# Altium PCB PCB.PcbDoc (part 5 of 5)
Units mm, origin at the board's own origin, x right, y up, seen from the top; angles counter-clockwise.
Board outline 101.6 x 53.34 mm, 6 copper layers (Top Layer, Int1 (GND), Int2, Int3, Int4 (GND), Bottom Layer), stack 1.625 mm thick; 228 components, 228 nets, 1016 pads, 998 vias.

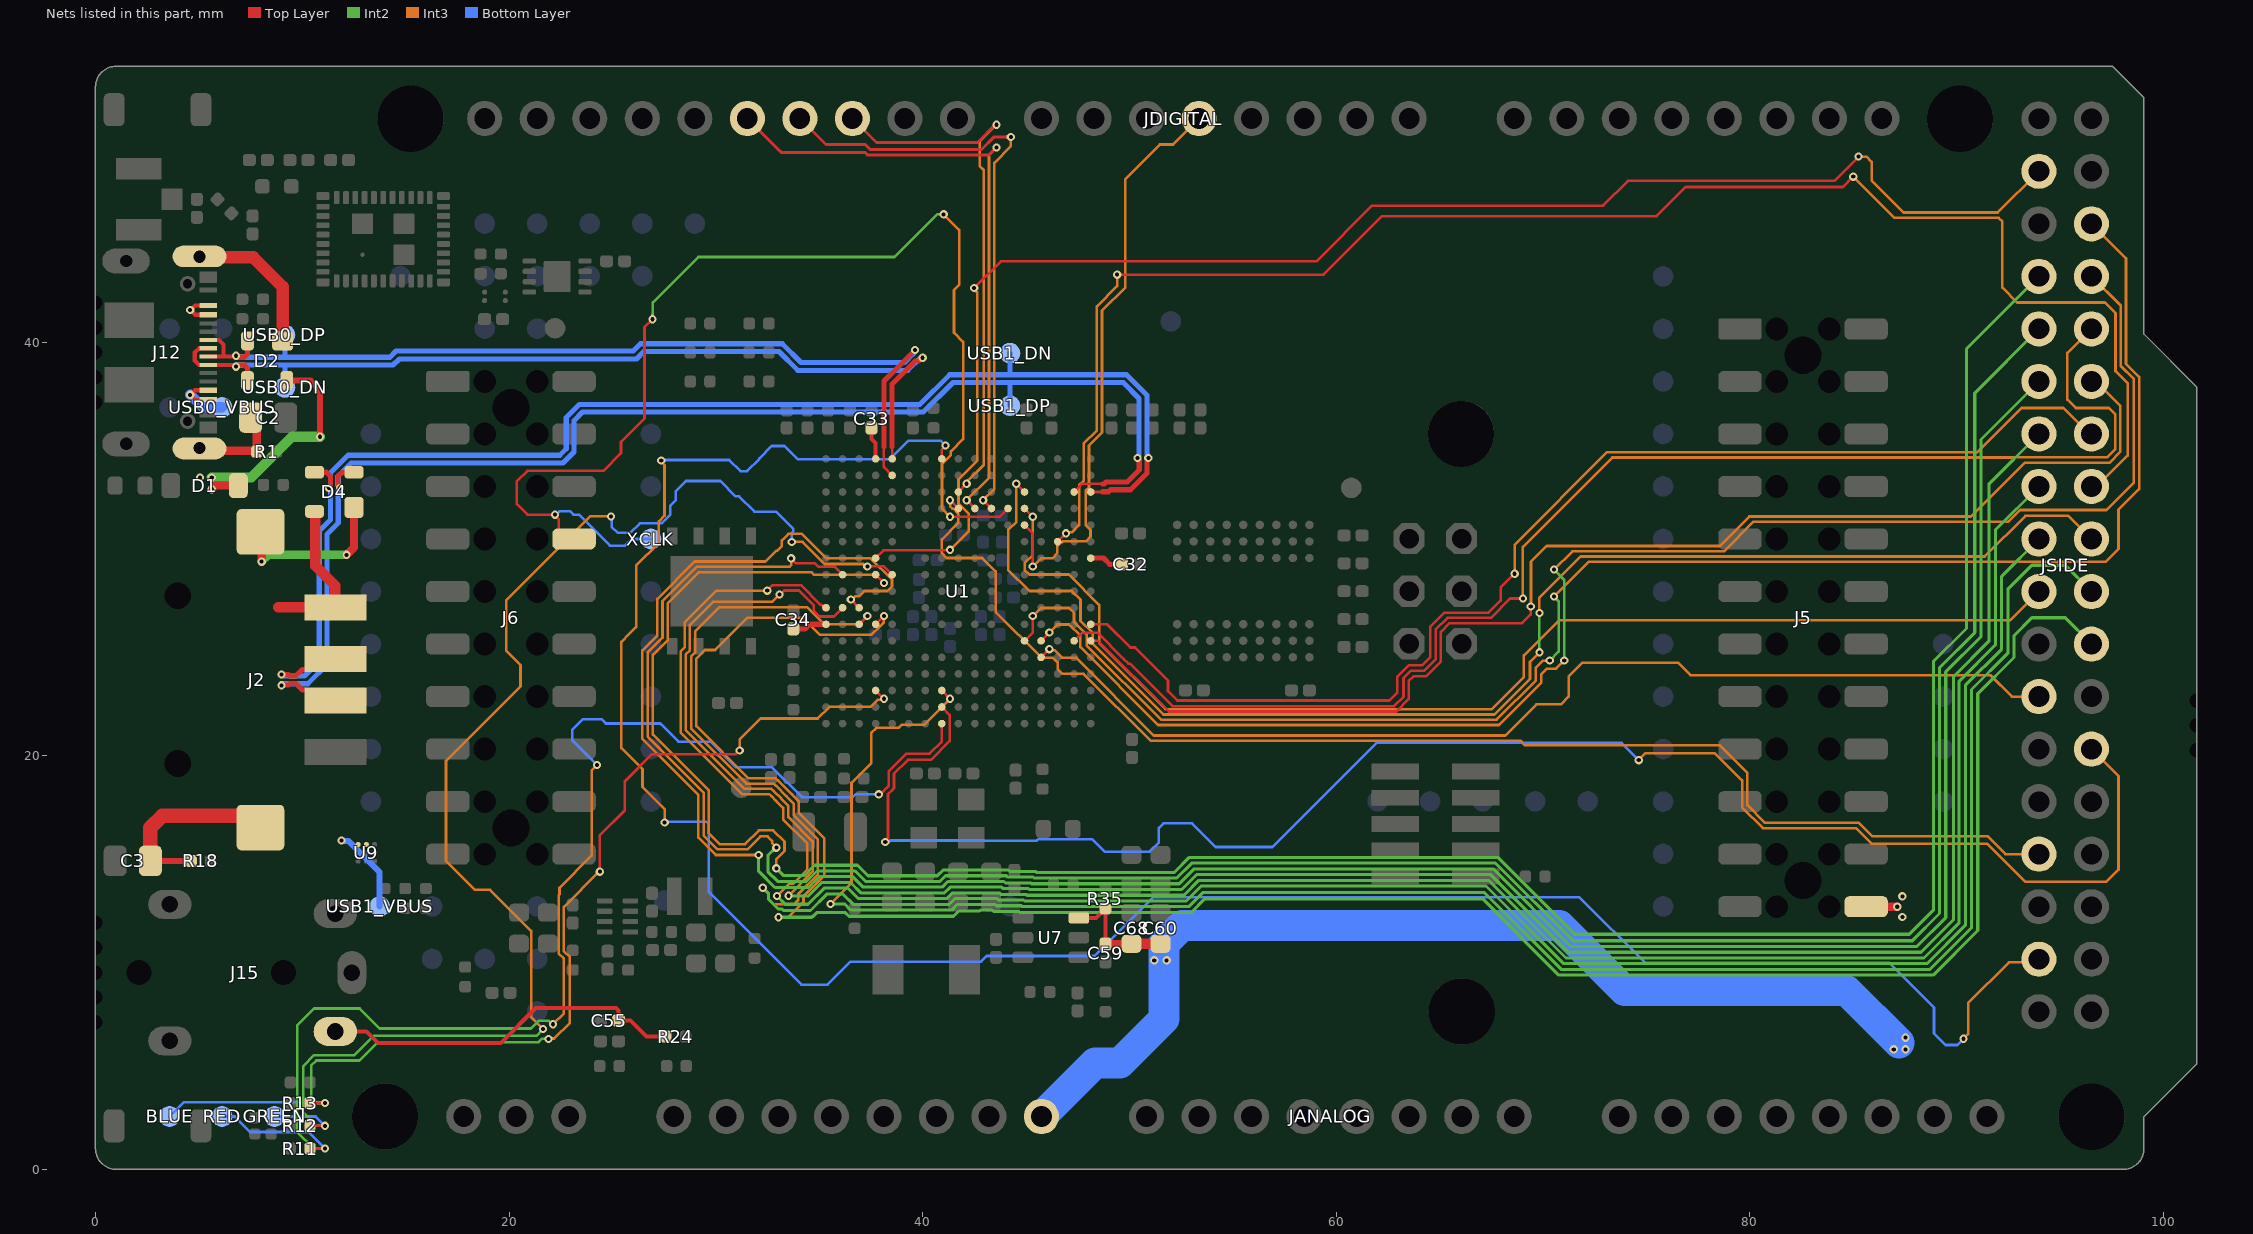
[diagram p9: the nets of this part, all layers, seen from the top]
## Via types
v1: diameter 0.4, hole 0.2, Top Layer to Bottom Layer, tented both sides, 998 vias

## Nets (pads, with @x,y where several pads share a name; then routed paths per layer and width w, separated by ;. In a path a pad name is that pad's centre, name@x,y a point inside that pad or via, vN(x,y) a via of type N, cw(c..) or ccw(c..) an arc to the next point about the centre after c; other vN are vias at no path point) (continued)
PI13: JSIDE.26 U1.H2 | length 82.6
  Top Layer w0.127: v1(38.192,15.823) 38.192,15.897 38.326,16.031 38.326,18.139 38.539,18.351 38.539,18.354 38.614,18.429 38.614,19.133 39.281,19.8 40.4,19.8 41.302,20.702 41.302,21.977 U1.H2@40.926,22.353
  Int3 w0.127: v1(74.626,19.785) 74.963,20.123 78.301,20.123 79.625,18.799 79.625,17.505 80.632,16.499 85.125,16.499 85.875,15.749 91.475,15.749 93.325,13.899 97.234,13.899 97.825,14.489 97.825,19.013 JSIDE.26@96.52,20.319
  Bottom Layer w0.127: v1(38.192,15.823) 38.244,15.875 38.417,15.875 38.44,15.898 42.903,15.898 42.909,15.892 45.514,15.892 45.59,15.967 48.188,15.967 48.8,15.356 50.971,15.356 51.418,15.802 51.418,16.515 51.634,16.732 53.023,16.732 54.169,15.586 56.911,15.586 61.943,20.618 73.793,20.618 v1(74.626,19.785)
PI14: JSIDE.20 U1.H3 | length 94.4
  Top Layer w0.127: U1.H3@40.926,23.153 v1(41.326,22.753)
  Int2 w0.15: v1(35.547,12.83) 36.234,12.83 36.529,12.534 41.402,12.534 41.679,12.811 42.684,12.811 43.477,12.812 43.547,12.742 44.765,12.742 44.809,12.698 52.866,12.698 53.543,13.376 67.172,13.376 70.882,9.667 88.713,9.667 90.722,11.675 90.722,23.199 92.474,24.952 92.474,28.047 93.636,29.209 95.25,29.209 JSIDE.20@96.52,27.939
  Int3 w0.127: v1(35.547,12.83) 36.042,13.324 36.56,13.842 36.56,18.686 37.505,19.632 37.505,21.091 37.76,21.346 38.84,21.346 38.987,21.493 40.067,21.493 v1(41.326,22.753)
PI15: JSIDE.23 U1.P5 | length 52.9
  Top Layer w0.127: U1.P5@45.726,24.753 v1(46.126,25.153)
  Int3 w0.127: v1(46.126,25.153) 46.177,25.102 46.373,25.102 46.732,24.743 47.407,24.743 51.174,20.977 68.177,20.977 69.682,22.481 70.86,22.481 71.235,22.856 71.235,23.836 71.897,24.499 76.525,24.499 77.125,23.899 91.625,23.899 92.665,22.859 JSIDE.23@93.98,22.859
PJ0: JSIDE.6 U1.N6 | length 79.6
  Top Layer w0.127: U1.N6@44.926,25.553 45.326,25.953 v1(45.326,26.753)
  Int2 w0.127: v1(70.325,24.599) 70.325,24.61 70.755,25.04 70.755,27.468 v1(70.525,27.699)
  Int3 w0.127: v1(45.326,26.753) 45.717,27.143 47.088,27.143 47.317,26.915 47.317,26.474 47.933,25.858 47.933,25.34 51.534,21.739 67.76,21.739 69.652,23.631 69.652,24.258 69.993,24.599 v1(70.325,24.599) ; v1(70.525,27.699) 72.205,29.378 97.205,29.378 97.825,29.999 97.825,31.899 98.823,32.896 98.823,38.318 98.19,38.951 98.19,44.049 JSIDE.6@96.52,45.719
PJ1: JSIDE.8 U1.P6 | length 74.7
  Top Layer w0.127: U1.P6@45.726,25.553 v1(46.126,25.953)
  Int2 w0.127: v1(70.525,28.999) 71.025,28.499 v1(71.025,24.599)
  Int3 w0.127: v1(46.126,25.953) 46.517,26.343 47.088,26.343 47.623,25.808 47.623,25.246 51.384,21.485 67.865,21.485 69.906,23.526 69.906,23.93 70.184,24.208 70.635,24.208 v1(71.025,24.599) ; v1(70.525,28.999) 71.413,29.886 78.746,29.886 80.175,31.315 92.504,31.315 93.071,31.882 97.235,31.882 98.569,33.216 98.569,38.213 97.936,38.846 97.936,41.763 JSIDE.8@96.52,43.179
PJ2: JSIDE.10 U1.T6 | length 68.2
  Top Layer w0.127: U1.T6@47.326,25.553 47.726,25.953 48.447,25.953 49.719,24.68 49.948,24.452 50.023,24.452 52.083,22.392 62.797,22.392 63.251,22.845 63.251,23.756 63.607,24.112 64.257,24.112 64.803,24.658 64.803,26.093 65.372,26.662 67.473,26.662 68.409,27.599 v1(69.025,27.599)
  Int3 w0.127: v1(69.025,27.599) 69.025,30.099 73.348,34.422 92.843,34.422 92.858,34.437 97.29,34.437 97.666,34.813 97.666,36.513 97.366,36.813 95.766,36.813 95.354,37.224 95.354,39.473 JSIDE.10@96.52,40.639
PJ3: JSIDE.12 U1.U6 | length 63.4
  Top Layer w0.127: U1.U6@48.126,25.553 48.487,25.553 51.903,22.138 62.903,22.138 63.505,22.74 63.505,23.607 63.739,23.841 64.345,23.841 65.057,24.553 65.057,25.988 65.477,26.408 68.985,26.408 69.404,26.827 v1(69.404,27.215)
  Int3 w0.127: v1(69.404,27.215) 69.416,27.227 69.416,29.389 70.167,30.14 78.547,30.14 79.976,31.569 90.696,31.569 93.291,34.164 97.381,34.164 97.92,34.703 97.92,36.909 96.73,38.099 JSIDE.12@96.52,38.099
PJ4: JSIDE.14 U1.U7 | length 59.1
  Top Layer w0.127: U1.U7@48.126,26.353 48.926,26.353 50.047,25.233 50.272,25.233 51.866,23.638 51.866,23.118 52.312,22.672 62.577,22.672 62.956,23.051 62.956,23.821 63.501,24.366 64.152,24.366 64.549,24.763 64.549,26.236 65.229,26.916 67.368,26.916 67.953,27.502 67.953,28.127 v1(68.625,28.799)
  Int3 w0.127: v1(68.625,28.799) 68.625,30.199 73.102,34.676 91.002,34.676 93.139,36.813 95.166,36.813 96.42,35.559 JSIDE.14@96.52,35.559
PJ5: JSIDE.16 U1.R12 | length 78.6
  Top Layer w0.127: U1.R12@46.526,30.353 v1(46.926,30.753) ; v1(49.406,43.261) 59.39,43.261 62.219,46.09 75.49,46.09 76.9,47.5 84.5,47.5 v1(85,48)
  Int3 w0.127: v1(46.926,30.753) 46.978,30.805 47.226,30.805 47.571,31.15 47.571,33.083 47.782,33.294 47.782,35.094 48.421,35.734 48.421,41.724 49.406,42.709 v1(49.406,43.261) ; v1(85,48) 86.988,46.012 92.029,46.012 92.21,45.83 92.21,42.63 92.928,41.913 97.166,41.913 97.682,41.396 97.682,38.596 98.266,38.013 98.266,34.513 96.772,33.019 JSIDE.16@96.52,33.019
PJ6: JSIDE.18 U1.N15 | length 67.6
  Top Layer w0.127: v1(44.526,33.153) 44.709,32.97 U1.N15@44.922,32.757
  Int2 w0.127: v1(69.825,24.999) v1(69.825,26.899)
  Int3 w0.127: v1(44.526,33.153) 44.526,31.305 44.136,30.915 44.136,28.991 45.164,27.962 47.088,27.962 47.099,27.974 47.205,27.974 47.635,27.543 47.635,26.515 48.226,25.924 48.226,25.407 51.639,21.993 67.655,21.993 69.368,23.706 69.368,24.542 v1(69.825,24.999) ; v1(69.825,26.899) 69.825,27.644 71.813,29.632 91.359,29.632 93.325,31.599 95.4,31.599 JSIDE.18@96.52,30.479
PJ7: JSIDE.19 U1.N14 | length 59.2
  Top Layer w0.127: U1.N14@44.926,31.953 v1(45.326,31.553)
  Int3 w0.127: v1(45.326,31.553) 45.326,29.705 44.936,29.315 44.936,28.991 45.164,28.762 47.069,28.762 48.539,27.292 48.539,25.452 51.745,22.247 67.526,22.247 69.075,23.796 69.075,24.849 70.775,26.548 92.59,26.548 JSIDE.19@93.98,27.939
PJ8: JDIGITAL.14 U1.N13 | length 28.7
  Top Layer w0.127: U1.N13@44.926,31.153 45.326,30.753 v1(45.326,29.153)
  Int3 w0.127: v1(45.326,29.153) 45.717,29.543 46.269,29.543 46.517,29.791 46.517,30.148 46.682,30.313 46.734,30.313 46.783,30.362 47.888,30.362 48.117,30.591 48.117,30.915 47.882,31.15 47.882,32.813 48.042,32.974 48.042,34.996 48.675,35.629 48.675,41.521 49.797,42.642 49.797,47.883 51.47,49.557 52.11,49.557 JDIGITAL.14@53.366,50.813
PJ9: J6.8 U1.M14 XCLK.X | length 58.3
  Top Layer w0.127: J6.8@22.863,30.5 22.822,30.5 22.411,30.911 22.411,31.427 22.217,31.62 v1(22.217,31.658) 20.891,31.658 20.38,32.169 20.38,33.275 20.881,33.775 24.555,33.775 25.412,34.633 25.412,35.179 26.547,36.314 26.547,40.72 v1(26.931,41.104) ; v1(41.326,31.553) 43.726,31.553 U1.M14@44.126,31.953
  Int2 w0.127: v1(26.931,41.104) 26.931,41.335 26.952,41.356 26.952,41.914 29.156,44.118 38.638,44.118 40.698,46.178 v1(41.016,46.178)
  Int3 w0.127: v1(41.016,46.178) 41.768,45.425 41.768,42.771 41.516,42.518 41.516,40.458 41.962,40.012 41.962,35.31 41.36,34.707 41.36,34.539 40.936,34.115 40.936,31.944 v1(41.326,31.553)
  Bottom Layer w0.127: v1(22.217,31.658) 22.274,31.658 22.428,31.812 22.963,31.812 23.117,31.658 23.383,31.658 24.88,30.16 25.603,30.16 25.921,30.479 XCLK.X@26.862,30.479
PJ10: JDIGITAL.7 U1.L14 | length 29.8
  Top Layer w0.127: v1(42.926,32.353) U1.L14@43.326,31.953
  Top Layer w0.15: JDIGITAL.7@34.062,50.813 35.322,49.552 37.227,49.552 37.462,49.317 42.843,49.317 43.439,49.913 v1(44.266,49.913)
  Int3 w0.127: v1(42.926,32.353) 43.462,32.889 43.462,48.668 44.266,49.471 v1(44.266,49.913)
PJ11: JDIGITAL.6 U1.K14 | length 31.2
  Top Layer w0.127: v1(42.126,32.353) U1.K14@42.526,31.953
  Top Layer w0.15: JDIGITAL.6@31.522,50.813 33.022,49.313 33.156,49.178 37.209,49.178 37.348,49.04 43.193,49.04 v1(43.566,49.413)
  Int3 w0.127: v1(42.126,32.353) 43.208,33.435 43.208,49.055 v1(43.566,49.413)
PJ12: JSIDE.3 U1.D11 | length 74
  Top Layer w0.127: U1.D11@37.726,29.553 38.102,29.928 41.302,29.928 v1(41.326,29.953) ; v1(42.49,42.613) 43.783,43.906 59.034,43.906 61.727,46.598 72.899,46.598 74.1,47.8 84.1,47.8 85.258,48.958 v1(85.258,48.971)
  Int3 w0.127: v1@41.326,29.953 42.226,30.853 42.226,31.701 41.736,32.191 41.736,33.363 42.635,34.262 42.635,42.402 42.49,42.547 v1(42.49,42.613) ; v1(85.258,48.971) 85.638,48.971 85.89,48.719 85.89,47.809 87.434,46.266 91.987,46.266 JSIDE.3@93.98,48.259
PJ14: JSIDE.7 U1.D10 | length 122
  Top Layer w0.127: U1.D10@37.726,28.753 v1(38.126,28.353)
  Int2 w0.15: v1(32.926,14.553) 33.281,14.198 34.268,14.198 34.772,14.703 36.852,14.703 37.358,14.196 40.714,14.196 40.991,14.473 41.997,14.473 ; 41.997,14.474 44.165,14.474 44.235,14.404 45.454,14.404 45.497,14.36 52.177,14.36 52.899,15.082 67.817,15.082 71.535,11.364 87.71,11.364 88.874,12.528 88.874,17.448 88.874,24.552 90.474,26.152 90.474,39.673 JSIDE.7@93.98,43.179
  Int3 w0.127: v1(32.926,14.553) 32.926,15.001 33.317,15.391 33.317,15.845 32.775,16.387 32.078,16.387 31.414,15.723 30.187,15.723 29.66,16.249 29.66,18.315 26.952,21.023 26.952,24.877 27.317,25.242 27.676,25.601 27.676,27.376 29.179,28.88 34.616,28.88 34.752,28.744 37.736,28.744 v1@38.151,28.328
PJ15: JSIDE.9 U1.B10 | length 118.6
  Top Layer w0.127: v1(33.642,29.544) 33.886,29.299 34.782,29.299 34.952,29.128 35.751,29.128 U1.B10@36.126,28.753
  Int2 w0.15: v1(32.926,15.553) 32.895,15.553 32.515,15.174 32.515,14.395 32.989,13.921 34.382,13.921 34.887,14.426 36.737,14.426 37.243,13.919 40.828,13.919 41.105,14.196 42.112,14.196 ; 42.112,14.197 44.051,14.197 44.12,14.127 45.339,14.127 45.383,14.083 52.292,14.083 53.013,14.805 67.702,14.805 71.455,11.052 87.855,11.052 89.174,12.371 89.174,24.252 90.874,25.952 90.874,37.533 JSIDE.9@93.98,40.639
  Int3 w0.127: 27.063,25.347 26.698,24.982 26.698,20.917 29.406,18.21 29.406,16.144 30.081,15.469 31.519,15.469 32.153,16.103 32.497,16.103 32.726,15.874 32.726,15.777 32.926,15.577 v1(32.926,15.553) ; 27.063,25.348 27.422,25.707 27.422,27.482 29.074,29.134 33.554,29.134 33.642,29.221 v1(33.642,29.544)
PK0: JSIDE.29 U1.J14 | length 64.9
  Top Layer w0.127: v1(41.326,32.353) U1.J14@41.726,31.953
  Int3 w0.127: v1@41.326,32.253 41.326,32.053 41.435,31.943 41.488,31.943 41.717,31.715 41.717,31.244 40.926,30.453 40.926,29.801 41.164,29.562 42.875,29.562 43.526,28.912 43.526,26.953 45.735,24.743 46.288,24.743 46.526,24.505 46.526,24.201 46.764,23.962 47.785,23.962 51.024,20.723 68.91,20.723 69.13,20.503 78.549,20.503 79.879,19.173 79.879,17.61 80.737,16.753 85.271,16.753 85.925,16.099 91.505,16.099 92.365,15.239 JSIDE.29@93.98,15.239
PK1: JDIGITAL.8 U1.J15 | length 26.5
  Top Layer w0.127: U1.J15@41.726,32.753 v1(42.126,33.153)
  Top Layer w0.15: JDIGITAL.8@36.602,50.813 37.765,49.65 42.655,49.65 43.518,50.513 v1(43.566,50.513)
  Int3 w0.127: v1(42.126,33.153) 42.126,33.227 42.954,34.055 42.954,48.317 42.753,48.518 42.753,49.7 v1(43.566,50.513)
PK2: JSIDE.33 U1.H17 | length 114.9
  Top Layer w0.127: U1.H17@40.926,34.353 40.926,34.801 41.1,34.975 v1(41.1,35)
  Int3 w0.127: v1(27.36,34.274) 27.36,34.215 27.517,34.059 27.517,31.61 27.24,31.333 27.24,30.293 26.145,29.198 26.145,26.226 25.793,25.874 25.428,25.508 25.428,20.367 26.45,19.346 26.45,18.493 27.524,17.419 v1(27.524,16.769) ; v1(90.334,6.31) 90.556,6.532 90.556,8.03 92.53,10.003 93.824,10.003 JSIDE.33@93.98,10.159
  Bottom Layer w0.127: v1(27.36,34.274) 27.385,34.299 30.641,34.299 31.184,33.756 31.507,33.756 32.105,34.354 32.105,34.379 32.702,34.977 33.318,34.977 33.951,34.343 38.429,34.343 39.318,35.232 40.868,35.232 v1(41.1,35) ; v1(27.524,16.769) 27.565,16.81 29.549,16.81 29.66,16.698 29.66,13.408 34.139,8.929 35.41,8.929 36.521,10.04 42.825,10.04 43.097,10.311 46.559,10.311 48.309,10.311 51.147,13.15 71.759,13.15 74.92,9.989 86.736,9.989 88.907,7.818 88.907,6.571 89.466,6.013 90.037,6.013 v1(90.334,6.31)
PK3: JSIDE.11 U1.C8 | length 122.4
  Top Layer w0.127: v1(36.526,27.553) U1.C8@36.926,27.153
  Int2 w0.15: v1(32.068,15.195) 32.068,14.411 32.851,13.629 33.16,13.629 33.681,13.629 34.481,13.629 35.001,14.149 36.622,14.149 37.129,13.642 40.943,13.642 41.22,13.919 42.226,13.919 43.936,13.92 44.006,13.85 45.224,13.85 45.268,13.806 52.407,13.806 53.128,14.528 67.588,14.528 71.341,10.775 88.078,10.775 89.474,12.171 89.474,24.052 91.174,25.752 91.174,35.293 JSIDE.11@93.98,38.099
  Int3 w0.127: 26.809,25.452 26.444,25.088 26.444,20.812 29.152,18.104 29.152,16.039 29.996,15.195 v1(32.068,15.195) ; 26.809,25.453 27.168,25.812 27.168,27.587 28.969,29.388 32.402,29.388 32.931,29.917 32.969,29.917 33.191,30.138 33.191,30.409 33.511,30.729 34.159,30.729 35.345,29.543 37.488,29.543 38.517,28.515 38.517,28.191 38.288,27.962 37.183,27.962 36.929,27.709 36.737,27.709 36.582,27.553 v1(36.526,27.553)
PK4: JSIDE.13 U1.B8 | length 110.6
  Top Layer w0.127: v1(33.082,27.797) 33.121,27.797 33.314,27.99 34.011,27.99 34.738,27.263 34.738,26.994 35.003,26.729 35.702,26.729 U1.B8@36.126,27.153
  Int2 w0.15: v1(33.515,13.227) 33.532,13.21 34.454,13.21 35.116,13.872 36.507,13.872 37.014,13.365 41.058,13.365 41.335,13.642 42.341,13.642 ; 42.342,13.643 43.821,13.643 43.891,13.573 45.109,13.573 45.153,13.529 52.521,13.529 53.243,14.251 67.473,14.251 71.226,10.498 88.279,10.498 89.845,12.063 89.845,23.822 91.574,25.552 91.574,33.153 JSIDE.13@93.98,35.559
  Int3 w0.127: v1(33.082,27.797) 32.725,27.44 29.85,27.44 28.741,26.331 28.741,25.098 28.549,24.907 28.549,21.222 31.375,18.396 32.685,18.396 32.784,18.297 32.793,18.297 33.171,17.92 33.171,17.911 33.504,17.578 33.504,17.027 34.678,15.853 34.678,14.39 v1(33.515,13.227)
PK5: JSIDE.15 U1.A8 | length 108.7
  Top Layer w0.127: v1(32.485,27.981) 32.748,28.244 34.116,28.244 35.061,27.299 35.114,27.299 35.26,27.153 U1.A8@35.326,27.153
  Int2 w0.15: v1(32.955,13.215) 33.355,12.814 34.459,12.814 35.239,13.595 36.393,13.595 36.899,13.088 41.173,13.088 41.45,13.365 42.456,13.365 43.706,13.366 43.776,13.296 44.995,13.296 45.038,13.252 52.636,13.252 53.357,13.973 67.359,13.973 71.111,10.221 88.419,10.221 90.122,11.923 90.122,23.599 91.874,25.352 91.874,30.913 JSIDE.15@93.98,33.019
  Int3 w0.127: v1(32.485,27.981) 30.032,27.981 28.487,26.436 28.487,25.237 28.293,25.044 28.293,21.118 31.27,18.142 32.58,18.142 32.679,18.043 32.688,18.043 32.917,17.815 32.917,17.805 33.25,17.473 33.25,16.922 34.424,15.748 34.424,14.495 33.749,13.821 33.556,13.821 32.955,13.219 v1(32.955,13.215)
PK6: JSIDE.17 U1.C7 | length 111.2
  Top Layer w0.127: U1.C7@36.926,26.353 v1(37.326,26.753)
  Int2 w0.15: v1(32.267,13.613) 32.553,13.327 32.553,13.048 33.013,12.587 33.194,12.587 33.233,12.548 33.241,12.548 33.272,12.517 34.573,12.517 35.363,13.306 36.149,13.306 36.644,12.811 41.287,12.811 41.564,13.088 42.57,13.088 ; 42.57,13.089 43.592,13.089 43.661,13.019 44.88,13.019 44.924,12.975 52.751,12.975 53.472,13.696 67.244,13.696 70.997,9.944 88.566,9.944 90.422,11.799 90.422,23.399 92.174,25.152 92.174,28.673 JSIDE.17@93.98,30.479
  Int3 w0.127: v1(32.267,13.613) 32.564,13.316 32.564,13.053 32.798,12.819 33.774,12.819 33.984,13.029 33.984,13.308 34.932,14.256 34.932,15.959 33.758,17.133 33.758,17.683 33.425,18.016 33.425,18.025 32.898,18.551 32.889,18.551 32.791,18.65 31.48,18.65 28.803,21.327 28.803,24.802 28.995,24.993 28.995,26.011 30.17,27.186 34.406,27.186 35.23,26.362 36.936,26.362 v1(37.326,26.753)
PK7: JSIDE.22 U1.D7 | length 109
  Top Layer w0.127: U1.D7@37.726,26.353 v1(38.126,26.753)
  Int2 w0.15: v1(33.034,12.185) 34.634,12.185 34.683,12.235 34.707,12.235 34.881,12.408 36.264,12.408 36.437,12.235 41.494,12.235 41.748,12.488 42.753,12.488 42.8,12.535 43.362,12.535 43.432,12.465 44.65,12.465 44.694,12.421 52.98,12.421 53.637,13.078 67.078,13.078 70.767,9.39 88.861,9.39 91.022,11.551 91.022,22.999 92.774,24.752 92.774,25.807 93.636,26.669 95.25,26.669 JSIDE.22@96.52,25.399
  Int3 w0.127: v1(33.034,12.185) 33.5,12.185 34.238,12.924 34.238,13.203 35.246,14.211 35.246,16.003 34.012,17.238 34.012,17.788 33.679,18.121 33.679,18.13 33.004,18.805 32.994,18.805 32.896,18.904 31.586,18.904 29.057,21.432 29.057,24.696 29.47,25.11 29.962,25.11 31.53,26.678 34.196,26.678 35.02,25.854 37.528,25.854 37.926,26.253 38.126,26.453 v1(38.126,26.753)
R_7: C55.2 J15.3 R24.2 | length 17.8
  Top Layer w0.2: J15.3@11.6,6.663 13.097,6.663 13.66,6.1 19.6,6.1 21.292,7.792 25.173,7.792 25.29,7.675 C55.2@25.29,7.19 25.87,7.19 26.641,6.419 R24.2@27.585,6.419
RGB_BLUE_1: BLUE.X R13.2 U1.D3 | length 52.3
  Top Layer w0.127: R13.2@10.375,3.2 v1(11.1,3.2) ; v1(24.389,14.392) 24.389,16.154 25.594,17.36 25.594,18.745 26.919,20.071 30.958,20.071 31.138,20.25 v1(31.15,20.25) ; U1.D3@37.726,23.153 v1(38.126,22.753)
  Int2 w0.127: v1(11.1,3.2) 10.71,3.2 10.43,3.48 10.43,5.011 10.68,5.261 12.761,5.261 13.65,6.15 21.422,6.15 21.577,6.304 v1(21.904,6.304)
  Int3 w0.127: v1(21.904,6.304) 21.925,6.325 22.182,6.325 22.936,7.079 22.936,10.257 22.65,10.543 22.65,12.694 24.348,14.392 v1(24.389,14.392) ; v1(31.15,20.25) 31.15,20.792 32.157,21.798 34.922,21.798 35.486,22.362 37.488,22.362 37.827,22.701 38.075,22.701 v1(38.126,22.753)
  Bottom Layer w0.127: BLUE.X@3.582,2.553 4.272,3.243 11.057,3.243 v1(11.1,3.2)
RGB_GREEN_1: GREEN.X R12.2 U1.E10 | length 69
  Top Layer w0.127: R12.2@10.375,2.1 v1(11.1,2.1) ; v1(37.326,29.153) 38.126,29.153 U1.E10@38.526,28.753
  Int2 w0.127: v1(11.1,2.1) 10.7,2.1 10.05,2.75 10.05,4.99 10.575,5.515 12.515,5.515 13.45,6.45 21.316,6.45 v1(21.644,6.779)
  Int3 w0.127: v1(21.644,6.779) 21.069,7.354 21.069,11.521 19.081,13.509 18.36,13.509 16.953,14.916 16.953,19.753 20.555,23.355 20.555,24.384 19.87,25.069 19.87,27.524 23.918,31.572 v1(24.933,31.572) ; v1(33.672,30.338) 34.191,30.338 35.26,29.269 37.136,29.269 37.252,29.153 v1(37.326,29.153)
  Bottom Layer w0.127: GREEN.X@8.662,2.553 10.647,2.553 v1(11.1,2.1) ; v1(24.933,31.572) 24.959,31.545 24.959,31.07 25.248,30.782 25.865,30.782 26.322,31.238 27.381,31.238 27.787,31.645 27.787,32.082 28.061,32.355 28.061,32.793 28.551,33.283 30.22,33.283 30.96,32.543 31.13,32.543 31.87,31.804 32.898,31.804 33.748,30.953 33.748,30.848 33.672,30.772 v1(33.672,30.338)
RGB_RED_1: R11.2 RED.X U1.H1 | length 64.4
  Top Layer w0.127: R11.2@10.375,1 v1(11.1,1) ; v1(37.877,18.132) 37.951,18.132 38.106,18.287 38.116,18.287 38.285,18.457 38.285,18.46 38.36,18.535 38.36,19.238 39.222,20.1 40.341,20.1 40.926,20.685 U1.H1@40.926,21.553
  Int2 w0.127: v1(11.1,1) 10.56,1 9.75,1.81 9.75,6.95 10.572,7.772 12.777,7.772 13.739,6.81 21.06,6.81 21.432,7.182 21.92,7.182 22.085,7.017 v1(22.127,7.017)
  Int3 w0.127: v1(22.127,7.017) 22.65,7.54 22.65,10.184 22.396,10.438 22.396,13.244 22.44,13.288 22.44,13.612 23.993,15.165 23.993,19.293 v1(24.25,19.55)
  Bottom Layer w0.127: RED.X@6.122,2.553 6.731,2.553 7.482,1.802 10.298,1.802 v1(11.1,1) ; v1(24.25,19.55) 23.05,20.75 23.05,21.25 23.567,21.767 24.47,21.767 24.681,21.555 27.31,21.555 27.335,21.531 27.344,21.531 28.193,20.682 29.736,20.682 30.98,19.438 32.725,19.438 34.173,17.991 36.618,17.991 36.759,18.132 v1(37.877,18.132)
SHIELD1a_3: C3.2 J2.SHIELD2 R18.2 | length 9.2
  Top Layer w0.3: C3.2@2.655,14.913 R18.2@4.731,14.913
  Top Layer w0.7: C3.2@2.655,14.913 2.655,16.519 3.24,17.105 J2.SHIELD2@7.92,17.105
SHIELD1b_3: D4.1 J2.SHIELD1 | length 8.2
  Top Layer w0.4: J2.SHIELD1@7.98,30.825 8.036,30.769 v1(8.036,29.383) ; v1(12.142,29.713) 12.501,30.072 D4.1@12.501,32.01
  Int2 w0.4: v1(8.036,29.383) 8.365,29.713 v1(12.142,29.713)
USB0_D_N: D2.3 J12.A7 J12.B7 U1.E17 USB0_DN.X | length 45.3
  Top Layer w0.127: 38.515,34.937 38.526,34.925 U1.E17@38.526,34.353
  Top Layer w0.2: J12.B7@5.454,39.7 5.008,39.7 4.802,39.494 4.802,39.106 5.008,38.9 J12.A7@5.454,38.9 6.657,38.9 6.746,38.812 v1(6.8,38.812)
  Top Layer w0.25: v1(6.8,38.812) 6.814,38.812 6.889,38.887 7.2,38.887 7.35,38.737 D2.3@7.35,38.145 ; 38.515,34.937 38.515,37.959 39.071,38.515 39.635,39.079 39.792,39.079 39.959,39.245 v1(40,39.245)
  Bottom Layer w0.25: v1@6.775,38.887 9.163,38.887 ; USB0_DN.X@9.163,37.809 9.163,38.887 ; v1(40,39.245) 39.971,39.217 39.865,39.217 39.283,38.635 33.96,38.635 33.052,39.542 26.515,39.542 26.163,39.19 14.695,39.19 14.391,38.887 9.163,38.887
USB0_D_P: D2.2 J12.A6 J12.B6 U1.E16 USB0_DP.X | length 45.9
  Top Layer w0.127: 38.138,34.937 38.126,34.925 38.126,33.953 U1.E16@38.526,33.553
  Top Layer w0.2: J12.B6@5.454,39.3 6.191,39.3 ; J12.A6@5.454,40.1 5.979,40.1 6.191,39.888 6.191,39.3 ; v1@6.707,39.3 6.191,39.3 ; v1@6.708,39.3 v1@6.87,39.3
  Top Layer w0.25: v1(6.8,39.339) 6.841,39.339 6.916,39.264 7.2,39.264 7.35,39.413 D2.2@7.35,40.055 ; 38.138,34.937 38.138,38.115 38.915,38.892 v1@39.627,39.604
  Bottom Layer w0.25: v1@6.775,39.264 9.163,39.264 ; USB0_DP.X@9.163,40.349 9.163,39.264 ; v1(39.627,39.618) 39.627,39.577 39.548,39.498 39.548,39.433 39.127,39.012 34.117,39.012 33.209,39.919 26.359,39.919 26.006,39.567 14.539,39.567 14.235,39.264 9.163,39.264
USB0_SHIELD1_3: D2.1 J12.SHIELD1 | length 7.2
  Top Layer w0.6: J12.SHIELD1@5.029,44.12 5.052,44.097 7.629,44.097 9.05,42.676 D2.1@9.05,40.055
USB0_SHIELD2_3: C2.2 J12.SHIELD2 R1.2 | length 4.7
  Top Layer w0.4: J12.SHIELD2@5.029,34.88 5.167,34.742 7.725,34.742 7.798,34.669 7.798,34.661 7.798,36.052 C2.2@7.5,36.35
USB1_D_N: D4.3 J2.2 U1.U15 USB1_DN.X | length 66.1
  Top Layer w0.127: U1.U15@48.126,32.753 48.698,32.753 48.71,32.764
  Top Layer w0.25: v1(9,23.927) 9.326,23.927 9.39,23.863 9.701,23.863 10.012,24.175 J2.2@11.6,24.175 ; D4.3@10.591,33.71 11.17,33.71 11.358,33.523 v1@11.358,33.125 ; 48.71,32.764 48.991,32.764 49.087,32.86 50.054,32.86 50.854,33.661 v1@50.854,34.222
  Bottom Layer w0.25: v1(9,23.927) 9.041,23.927 9.116,23.852 10.111,23.852 10.822,24.563 10.822,30.869 11.366,31.413 11.366,32.828 11.287,32.907 v1(11.287,32.948) 11.287,32.988 11.366,33.068 11.366,33.679 12.216,34.529 18.792,34.529 22.454,34.529 22.767,34.841 22.767,36.357 23.4,36.99 39.877,36.99 41.309,38.422 44.161,38.422 ; USB1_DN.X@44.221,39.463 44.221,38.482 44.161,38.422 ; v1(50.912,34.392) 50.884,34.421 50.884,34.527 50.844,34.566 50.844,35.272 50.844,37.431 49.854,38.422 44.161,38.422
USB1_D_P: D4.2 J2.3 U1.T15 USB1_DP.X | length 66.1
  Top Layer w0.127: U1.T15@47.326,32.753 47.726,33.153 48.698,33.153 48.71,33.141
  Top Layer w0.25: v1(9,23.4) 9.021,23.421 9.325,23.421 9.39,23.486 9.701,23.486 10.012,23.175 J2.3@11.6,23.175 ; v1(11.822,32.948) 11.822,32.988 11.735,33.076 11.735,33.523 11.922,33.71 D4.2@12.501,33.71 ; 48.71,33.141 48.777,33.141 48.873,33.237 49.898,33.237 50.477,33.817 v1@50.477,34.26
  Bottom Layer w0.25: v1(9,23.4) 9.041,23.4 9.116,23.475 10.268,23.475 11.199,24.406 11.199,30.713 11.743,31.257 11.743,32.828 11.822,32.907 v1(11.822,32.948) 11.822,32.988 11.743,33.068 11.743,33.523 12.372,34.152 18.636,34.152 22.61,34.152 23.144,34.685 23.144,36.201 23.556,36.613 40.033,36.613 41.465,38.045 44.261,38.045 ; USB1_DP.X@44.221,36.923 44.221,38.005 44.261,38.045 ; v1(50.385,34.392) 50.385,34.433 50.467,34.515 50.467,35.428 50.467,37.275 49.698,38.045 44.261,38.045
VBUS_USB0: D1.A D2.4 J12.A4 J12.A9 J12.B4 J12.B9 USB0_VBUS.X | length 17.1
  Top Layer w0.2: J12.A9@5.454,37.225 4.804,37.225 v1(4.579,37.45) 4.804,37.675 J12.B4@5.454,37.675 ; J12.B9@5.454,41.325 4.804,41.325 v1(4.579,41.55) 4.804,41.775 J12.A4@5.454,41.775
  Top Layer w0.3: D2.4@9.25,38.145 10.384,38.145 10.854,37.675 v1(10.854,35.425)
  Top Layer w0.4: v1(5.622,32.887) 5.797,33.062 D1.A@6.91,33.062
  Int2 w0.5: v1(5.622,33.453) 7.532,33.453 9.504,35.425 v1(10.854,35.425)
  Bottom Layer w0.5: v1(4.579,37.45) 5.186,36.843 USB0_VBUS.X@6.122,36.843
  other v1: 5.056,33.453
VBUS_USB1: D4.4 J2.1 U9.A3 U9.B3 USB1_VBUS.X | length 11.9
  Top Layer w0.5: 8.825,27.175 J2.1@11.6,27.175 11.6,28.213 10.622,29.191 D4.4@10.622,31.81
  Bottom Layer w0.3: v1(11.9,15.9) 11.919,15.881 12.231,15.881 13.742,14.37 USB1_VBUS.X@13.742,12.713
VCAP_A7_5: C34.2 U1.A7 | length 1.7
  Top Layer w0.25: C34.2@33.746,26.133 34.306,26.133 34.526,26.353 U1.A7@35.326,26.353
VCAP_D17_5: C33.2 U1.D17 | length 1.5
  Top Layer w0.2: C33.2@37.532,35.747 37.532,35.317 37.726,35.123 U1.D17@37.726,34.353
VCAP_U11_5: C32.2 U1.U11 | length 1.6
  Top Layer w0.25: U1.U11@48.126,29.553 48.745,29.553 49.045,29.253 C32.2@49.621,29.253
VIN: C59.1 C60.2 C68.2 J5.24 JANALOG.8 R35.1 U7.3 | length 57.9
  Top Layer w0.2: U7.3@47.55,12.15 48.384,12.15 R35.1@48.831,12.597 ; C59.1@48.842,10.894 R35.1@48.842,12.587 ; 49.206,10.903 C68.2@50.1,10.903
  Top Layer w0.4: C59.1@48.842,10.894 50.091,10.894 C68.2@50.1,10.903 ; J5.24@85.725,12.699 v1(87.125,12.699)
  Top Layer w0.5: C68.2@50.1,10.903 C60.2@51.5,10.903
  Bottom Layer w1.5: JANALOG.8@45.755,2.562 48.337,5.144 49.539,5.144 51.672,7.277 51.672,10.923 52.548,11.799 70.787,11.799 73.944,8.642 84.682,8.642 87.205,6.119
  other v1: 86.96,5.799 87.525,5.799 87.525,6.364 51.2,10.104 51.8,10.104 87.375,12.199 87.375,13.199
pads on no net: Fiducial_1.1 Fiducial_2.1 Fiducial_3.1 Fiducial_4.1 Fiducial_5.1 J2.HOLES J5.0 J6.0 J8.6 J8.7 J8.8 J12.A8 J12.B8 J12.FIXING J12.SHIELD3 J12.SHIELD4 J15.NC1 J15.NC2 JANALOG.1 U1.E1 U3.E2 U4.1 U4.2 U4.3 U4.7 U4.9 U5.6 U5.7 U5.8 U5.9 U5.10 U5.11 U5.13 U5.15 U5.16 U5.17 U5.18 U6.6 U9.C1 Y3.2 Y3.4

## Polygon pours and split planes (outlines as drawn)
GND on Int2 "GND_L03_P012" (solid, remove dead copper, pour order 12): 0,1 0,52.34 cw(c1,52.34) 1,53.34 97.536,53.34 99.06,51.816 99.06,40.386 101.6,37.846 101.6,5.08 99.06,2.54 99.06,1 cw(c98.06,1) 98.06,0 1,0 cw(c1,1)
+3V3 on Int2 "+3V3_L03_P003" (solid, remove dead copper, pour order 3): 11.483,48.43 13.31,48.43 16.81,44.93 30.443,44.93 37.256,38.256 37.278,35.434 32.335,29.413 25.642,29.413 22.919,32.135 22.919,38.421 22.11,39.23 20.21,39.23 18.22,39.23 17.648,38.644 17.648,37.106 17.272,36.73 15.61,36.73 14.337,38.003 14.337,41.113 12.737,42.713 11.842,42.713 11.342,43.213 11.342,45.013 10.573,45.613 10.573,47.672
+3V3 on Int2 "+3V3_L03_P011" (solid, remove dead copper, pour order 11): 31.5,35.5 33,37 58,37 61,34 61,23.5 54,17.5 51.5,17.5 48.485,14.485 40.895,14.485 38.274,11.812 33.874,7.412 29.074,7.412 25.522,10.964 25.522,29.522
VBUS_USB0 on Int2 "VBUS_USB0_L03_P001" (solid, remove dead copper, pour order 1): 2.274,40.836 2.274,33.43 3.151,32.553 6.067,32.553 6.067,35.8 6.067,42.1 3.538,42.1
+5V on Int2 "+5V_L03_P032" (solid, remove dead copper, pour order 32): 97.11,52.43 98.21,51.33 98.21,47.03 97.182,46.002 88.21,46.002 88.21,48 90.279,48 93.78,51.5 93.78,52.172 94.038,52.43
GND on Top Layer "GND_L01_P036" (solid, remove dead copper, pour order 36): 0,1 0,52.34 cw(c1,52.34) 1,53.34 97.536,53.34 99.06,51.816 99.06,40.386 101.6,37.846 101.6,5.08 99.06,2.54 99.06,1 cw(c98.06,1) 98.06,0 1,0 cw(c1,1)
+5V on Top Layer "+5V_L01_P021" (solid, remove dead copper, pour order 21): 36.916,11.776 36.916,10.853 37.253,10.516 37.253,7.89 37.116,7.753 36.216,7.753 36.016,7.953 36.016,10.353 36.516,10.853 36.516,11.776
+3V3 on Top Layer "+3V3_L01_P019" (solid, pour order 19): 32.074,10.341 32.074,9.385 32.159,9.3 32.324,9.135 32.324,8.074 32.15,7.9 31.4,7.9 31.15,8.15 31.15,9.15 31.3,9.3 31.589,9.3 31.674,9.385 31.674,10.341
+3V3 on Top Layer "+3V3_L01_P029" (solid, remove dead copper, pour order 29): 76.675,14.088 76.675,13.695 77.372,12.999 79.86,12.999 79.86,12.413 76.213,12.413 74.913,13.713 74.913,14.101 75.056,14.245 76.519,14.245
VIN on Top Layer "VIN_L01_P025" (solid, remove dead copper, pour order 25): 85.725,12.999 86.825,12.999 87.225,13.399 87.725,13.399 87.925,13.199 87.925,12.199 87.725,11.999 87.225,11.999 86.825,12.399 85.725,12.399
+5V on Top Layer "+5V_L01_P022" (solid, remove dead copper, pour order 22): 77.874,16.19 77.874,15.797 78.219,15.452 79.874,15.452 79.874,14.952 76.974,14.952 76.112,15.814 76.112,16.203 76.255,16.347 77.718,16.347
VBUS_USB1 on Top Layer "POWER_POLY" (solid, remove dead copper, pour order 7): 12.4,27.8 12.4,26.547 9.247,26.547 7.832,25.132 7.832,22.868 11.706,18.994 12.268,18.994 13.3,17.962 13.3,15.9 13.085,15.685 9.415,15.685 5.9,19.2 5.9,26.156 7.544,27.8 10.5,27.8
+5V on Top Layer "+5V_L01_P004" (solid, remove dead copper, pour order 4): 97.266,52.598 98.205,51.659 98.205,47.876 97.266,46.913 91.942,46.913 91.742,46.713 90.242,46.713 90.142,46.813 90.142,47.613 90.442,47.913 91.112,47.913 92.832,49.633 92.832,51.84 93.59,52.598
VBUS_USB0 on Top Layer "VBUS_USB0_L01_P016" (solid, remove dead copper, pour order 16): 4.822,33.753 5.822,33.753 6.222,33.353 7.022,33.353 7.022,32.753 6.222,32.753 6.022,32.553 5.222,32.553 4.622,33.153 4.622,33.553
+5V on Top Layer "+5V_L01_P034" (solid, remove dead copper, pour order 34): 20.628,12.636 20.628,12.179 19.648,12.179 19.178,11.709 18.978,11.509 17.978,11.509 17.778,11.709 17.778,12.477 17.937,12.636
+5V on Top Layer "+5V_L01_P030" (solid, remove dead copper, pour order 30): 3.857,33.213 3.857,32.213 4.357,31.713 4.357,30.813 4.162,30.618 3.151,30.618 2.957,30.813 2.957,31.713 3.457,32.213 3.457,33.213
+3V3 on Top Layer "+3V3_FLASH" (solid, remove dead copper, pour order 17): 55.995,28.595 56.707,28.595 58.888,30.776 60.5,30.776 60.542,24.713 60.242,24.413 58.278,24.413 57.94,24.75 55.15,24.75 55.15,28.6
GND on Int3 "GND_L04_P035" (solid, remove dead copper, pour order 35): 0,1 0,52.34 cw(c1,52.34) 1,53.34 97.536,53.34 99.06,51.816 99.06,40.386 101.6,37.846 101.6,5.08 99.06,2.54 99.06,1 cw(c98.06,1) 98.06,0 1,0 cw(c1,1)
+5V on Int3 "NONET_L-01_P-001" (solid, remove dead copper, pour order 18): 4.1,32.2 4.9,31.4 4.9,16.7 6.5,15.1 16.4,15.1 17.6,13.9 16.2,12.5 5,12.5 2.1,15.4 2.1,31.4 2.9,32.2
VIN on Int3 "VIN_L04_P027" (solid, remove dead copper, pour order 27): 87.925,13.199 87.925,5.793 87.664,5.531 86.866,5.531 86.625,5.772 86.625,13.199 86.825,13.399 87.725,13.399
GND on Int1 (GND) "GND_L02_P000" (solid, remove dead copper, pour order 0): 0,1 0,52.34 cw(c1,52.34) 1,53.34 97.536,53.34 99.06,51.816 99.06,40.386 101.6,37.846 101.6,5.08 99.06,2.54 99.06,1 cw(c98.06,1) 98.06,0 1,0 cw(c1,1)
GND on Int4 (GND) "GND_L05_P028" (solid, remove dead copper, pour order 28): 0,1 0,52.34 cw(c1,52.34) 1,53.34 97.536,53.34 99.06,51.816 99.06,40.386 101.6,37.846 101.6,5.08 99.06,2.54 99.06,1 cw(c98.06,1) 98.06,0 1,0 cw(c1,1)
GND on Bottom Layer "GND_L06_P026" (solid, remove dead copper, pour order 26): 0,1 0,52.34 cw(c1,52.34) 1,53.34 97.536,53.34 99.06,51.816 99.06,40.386 101.6,37.846 101.6,5.08 99.06,2.54 99.06,1 cw(c98.06,1) 98.06,0 1,0 cw(c1,1)

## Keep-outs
Top Layer:
  rectangle: 18.226,41.504 20.093,42.57
  lines w0.2: 49.613,10.197 49.756,10.197 50.602,9.351 52.209,9.351 52.538,9.68 52.538,11.544 52.356,11.727 52.356,13.934

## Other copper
Top Layer:
  region net VIN: 51.935,11.103 51.935,10.446 52.129,10.252 52.129,9.771 51.5,9.771 50.871,9.771 50.871,10.252 51.065,10.446 51.065,11.103 51.5,11.103
Bottom Layer:
  text "V1.2" at 11.75,50.2 h1.2

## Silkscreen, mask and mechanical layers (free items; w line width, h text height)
Top Overlay:
  drawing of 429 lines, arcs and shapes, not listed
Bottom Overlay:
  drawing of 248 lines, arcs and shapes, not listed
Route Tool Path:
  lines w2: -1,6.513 -1,6.313 -1,3 -1,1 ccw(c1,1) 1,-1 98.06,-1 ccw(c98.06,1) 100.06,1 100.06,2.126 102.307,4.373 ; -1,12.513 -1,14.313 -1,35.2 -1,36.5 ; -1,42.5 -1,43.2 -1,50 -1,52.34 cw(c1,52.34) 1,54.34 97.536,54.34 ; 102.6,19.663 102.6,5.08 ; 102.6,23.263 102.6,37.346 ; 102.6,35.846 102.6,37.846 ; 97.536,54.34 cw(c97.536,53.34) 98.243,54.047 ; 97.536,54.34 cw(c97.536,53.34) 98.243,54.047 ; 98.243,54.047 99.767,52.523 ; 99.767,52.523 cw(c99.06,51.816) 100.06,51.816 ; 99.767,52.523 cw(c99.06,51.816) 100.06,51.816 ; 100.06,51.816 100.06,40.8 102.307,38.553 ; 102.307,4.373 ccw(c101.6,5.08) 102.6,5.08 ; 102.307,4.373 ccw(c101.6,5.08) 102.6,5.08 ; 102.307,38.553 cw(c101.6,37.846) 102.6,37.846 ; 102.307,38.553 cw(c101.6,37.846) 102.6,37.846
Board:
  the board outline again, w0.254
GigaShieldDesign:
  drawing of 255 lines, arcs and shapes, not listed
Silk_ee:
  drawing of 54 lines, arcs and shapes, not listed
  text "RESET" at 7.297,48.564 h1.2 r90
  text "9" at 39.834,48.26 h1.8 r90
  text "8" at 42.374,48.26 h1.8 r90
  text "11" at 34.754,47.676 h1.8 r90
  text "12" at 32.214,47.494 h1.8 r90
  text "10" at 37.294,47.492 h1.8 r90
  text "22" at 90.67,47.494 h1.8
  text "13" at 29.746,47.279 h1.8 r90
  text "7" at 46.485,47.083 h1.8 r90
  text "6" at 49.025,47.083 h1.8 r90
  text "5" at 51.565,47.083 h1.8 r90
  text "4" at 54.105,47.083 h1.8 r90
  text "3" at 56.645,47.083 h1.8 r90
  text "2" at 59.185,47.083 h1.8 r90
  text "1" at 61.725,47.083 h1.8 r90
  text "0" at 64.265,47.083 h1.8 r90
  text "14" at 69.345,47.083 h1.8 r90
  text "15" at 71.885,47.083 h1.8 r90
  text "16" at 74.425,47.083 h1.8 r90
  text "17" at 76.965,47.083 h1.8 r90
  text "18" at 79.505,47.083 h1.8 r90
  text "19" at 82.045,47.083 h1.8 r90
  text "20" at 84.585,47.083 h1.8 r90
  text "21" at 87.125,47.083 h1.8 r90
  text "SCL1" at 19.514,45.098 h1.8 r90
  text "24" at 90.67,44.954 h1.8
  text "SDA1" at 22.054,44.918 h1.8 r90
  text "AREF" at 24.594,44.586 h1.8 r90
  text "26" at 90.67,42.414 h1.8
  text "SCK" at 29.721,41.393 h1.8 r90
  text "CIPO" at 32.261,41.393 h1.8 r90
  text "COPI" at 34.801,41.393 h1.8 r90
  text "CS" at 37.341,41.393 h1.8 r90
  text "SDA3" at 39.881,41.393 h1.8 r90
  text "SCL3" at 42.421,41.393 h1.8 r90
  text "TX0" at 61.725,41.393 h1.8 r90
  text "RX0" at 64.265,41.393 h1.8 r90
  text "TX3" at 69.345,41.393 h1.8 r90
  text "RX3" at 71.885,41.393 h1.8 r90
  text "TX2" at 74.425,41.393 h1.8 r90
  text "RX2" at 76.965,41.393 h1.8 r90
  text "TX1" at 79.505,41.393 h1.8 r90
  text "RX1" at 82.045,41.393 h1.8 r90
  text "SDA2" at 84.585,41.393 h1.8 r90
  text "SCL2" at 87.125,41.393 h1.8 r90
  text "D1N" at 74.851,39.874 h1.8
  text "D1P" at 87.06,39.874 h1.8
  text "28" at 90.67,39.874 h1.8
  text "3V3" at 12.904,37.334 h1.8
  text "30" at 90.67,37.334 h1.8
  text "31" at 98.19,37.334 h1.8
  text "USB0" at 9.666,36.7 h1.8 r90
  text "SCL1" at 11.843,34.794 h1.8
  text "SDA1" at 24.602,34.794 h1.8
  text "CKN" at 74.815,34.794 h1.8
  text "CKP" at 87.06,34.794 h1.8
  text "32" at 90.67,34.794 h1.8
  text "33" at 98.19,34.794 h1.8
  text "54" at 13.842,32.254 h1.8
  text "55" at 24.602,32.254 h1.8
  text "34" at 90.67,32.254 h1.8
  text "35" at 98.19,32.254 h1.8
  text "56" at 13.842,29.714 h1.8
  text "57" at 24.602,29.714 h1.8
  text "D0N" at 75.123,29.714 h1.8
  text "D0P" at 87.06,29.714 h1.8
  text "36" at 90.67,29.714 h1.8
  text "37" at 98.19,29.714 h1.8
  text "58" at 13.842,27.174 h1.8
  text "59" at 24.602,27.174 h1.8
  text "38" at 90.67,27.174 h1.8
  text "39" at 98.19,27.174 h1.8
  text "60" at 13.842,24.634 h1.8
  text "61" at 24.602,24.634 h1.8
  text "68" at 76.325,24.634 h1.8
  text "69" at 87.085,24.634 h1.8
  text "40" at 90.67,24.634 h1.8
  text "41" at 98.19,24.634 h1.8
  text "62" at 13.842,22.094 h1.8
  text "63" at 24.602,22.094 h1.8
  text "70" at 76.325,22.094 h1.8
  text "71" at 87.085,22.094 h1.8
  text "42" at 90.67,22.094 h1.8
  text "43" at 98.19,22.094 h1.8
  text "USB1" at 9.666,20.675 h1.8 r90
  text "64" at 13.842,19.554 h1.8
  text "65" at 24.602,19.554 h1.8
  text "72" at 76.325,19.554 h1.8
  text "73" at 87.085,19.554 h1.8
  text "44" at 90.67,19.554 h1.8
  text "45" at 98.19,19.554 h1.8
  text "74" at 76.325,17.014 h1.8
  text "75" at 87.085,17.014 h1.8
  text "46" at 90.67,17.014 h1.8
  text "47" at 98.19,17.014 h1.8
  text "66" at 12.267,15.759 h1.8
  text "67" at 26.402,15.759 h1.8
  text "3V3" at 75.387,14.474 h1.8
  text "48" at 90.67,14.474 h1.8
  text "49" at 98.19,14.474 h1.8
  text "5V" at 75.545,11.934 h1.8
  text "VIN" at 87.06,11.934 h1.8
  text "50" at 90.67,11.934 h1.8
  text "51" at 98.19,11.934 h1.8
  text "52" at 90.67,9.394 h1.8
  text "53" at 98.19,9.394 h1.8
  text "GIGA" at 52.768,8.24 h4
  text "AUDIO / IN/OUT" at 19.343,7.244 h1.8 r90
  text "OFF" at 19.083,4.349 h1.8 r90
  text "VRTC" at 24.163,4.349 h1.8 r90
  text "IOREF" at 31.245,4.349 h1.8 r90
  text "RESET" at 33.785,4.349 h1.8 r90
  text "3V3" at 36.325,4.349 h1.8 r90
  text "5V" at 38.865,4.349 h1.8 r90
  text "VIN" at 46.485,4.349 h1.8 r90
  text "A0" at 51.565,4.349 h1.8 r90
  text "A1" at 54.105,4.349 h1.8 r90
  text "A2" at 56.645,4.349 h1.8 r90
  text "A3" at 59.185,4.349 h1.8 r90
  text "A4" at 61.722,4.351 h1.8 r90
  text "A5" at 64.265,4.349 h1.8 r90
  text "A6" at 66.805,4.349 h1.4 r90
  text "A7" at 69.345,4.349 h1.8 r90
  text "A8" at 74.425,4.349 h1.8 r90
  text "A9" at 76.965,4.349 h1.8 r90
  text "A10" at 79.505,4.349 h1.8 r90
  text "A11" at 82.045,4.349 h1.8 r90
  text "DAC2" at 84.585,4.349 h1.8 r90
  text "DAC1" at 87.125,4.349 h1.8 r90
  text "CANRX" at 89.665,4.349 h1.5 r90
  text "CANTX" at 92.205,4.349 h1.5 r90
  text "BOOT0" at 7.297,-0.576 h1.2 r90
GIGA test points:
  drawing of 828 lines, arcs and shapes, not listed
  text "GND" at 25.766,49.603 h0.5 r180
  text "DSI" at 74.739,42.948 h0.5
  text "DSI" at 74.739,40.408 h0.5
  text "DSI" at 74.739,37.868 h0.5
  text "DSI" at 74.739,35.328 h0.5
  text "DSI" at 74.739,32.788 h0.5
  text "5V" at 68.289,30.267 h0.5
  text "DSI" at 74.739,30.248 h0.5
  text "GND" at 74.739,27.708 h0.5
  text "GND" at 68.289,25.187 h0.5
  text "BOOT" at 22.366,20.903 h2 r90
  text "3V3" at 62.666,18.803 h0.5
  text "GND" at 72.866,18.803 h0.5
  text "5V" at 74.739,15.008 h0.5
  text "3V3" at 74.739,12.468 h0.5
  text "GND" at 91.466,7.903 h0.5 r180
  text "GND" at 97.766,7.803 h0.5 r180
  text "3V3" at 29.784,4.278 h0.5 r180
  text "3V3" at 34.864,4.278 h0.5 r180
  text "5V" at 37.474,4.278 h0.5 r180
  text "GND" at 40.014,4.278 h0.5 r180
  text "GND" at 42.554,4.278 h0.5 r180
